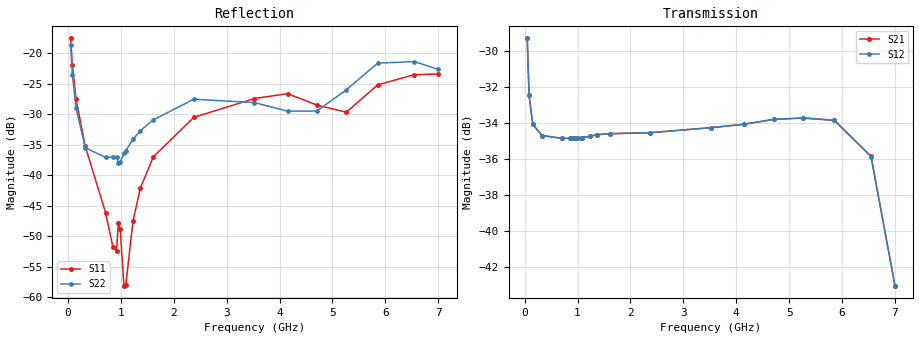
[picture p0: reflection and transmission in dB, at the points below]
! Integrated Device Technology
! Corporate Headquarters
! 6024 Silver Creek Valley Road
! San Jose, CA 95138  USA
! Phone:  1-408-284-8200
! Toll Free:  1-800-223-1366
! Webpage:  http://www.idt.com/
! Timing and RF Division
! 515 Groton Road, Suite 102
! Westford, MA 01886-6024
! Device:  F2258
! Description: Voltage Variable RF Attenuator
! Frequency:  50.0 -  6000.00 MHz
! Package:  3x3 mm Thin QFN Plastic Package: 16 pin
! Ports:  2 RF, 2 DC
!  Pin  1  = NC
!  Pin  2  = NC
!  Pin  3  = RF2  = Port 2
!  Pin  4  = GND
!  Pin  5  = Vdd
!  Pin  6  = NC
!  Pin  7  = VCTRL
!  Pin  8  = NC
!  Pin  9  = GND
!  Pin 10  = RF1  = Port 1
!  Pin 11  = NC
!  Pin 12  = NC
!  Pin 13  = NC
!  Pin 14  = NC
!  Pin 15  = NC
!  Pin 16  = NC
! Vcntrl:  1.960 Volts
! Vdd:  +3.300 Volts
! Current:  1.155 mA
! Data:  The device was measured on a the F2258 evaluation board which has
!  individual transmission lines to the RF pins.  Data was collected
!  using a calibrated network analyzer.  The evaluation board was
!  de-embedded using a TRL calibration technique.
!  The reference plane is the edge of the package pin.
! Misc:  SN 10
!  Action Tracker AT0285
! Date Measured:  2014-12-10
! Date:  2016-01-13  MJV
! Note:
!  Integrated Device Technology supplies this data as a sample of measured
!  data at the package pin for this product.  Your particular data for this
!  product may vary.
!  Data was taken at 25 degrees C.
!  Integrated Device Technology reserves the right to change this data at anytime.
!Freq_(GHz)  S11M_(dB)  S11P_(deg)  S21M_(dB)  S21P_(deg)  S12M_(dB)  S12P_(deg)  S22M_(dB)  S22P_(deg)
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# GHz S dB R 50
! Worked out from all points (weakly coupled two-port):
!   201 points, 50 MHz to 7 GHz, reference 50 ohm
!   highest |S21| = -29.28 dB at 50 MHz (marker M1); lowest = -43.0 dB at 7 GHz (marker M2)
!   lowest |S11| = -58.1 dB at 1.058 GHz (marker M3), VSWR 1.00, Z = 49.9 + j0.0533 ohm
!   |S11| at or under -10 dB: start of sweep to end of sweep
!   |S22| runs from -38.1 to -18.7 dB; largest |S21 - S12| = 6.1e-05
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0.05  -17.55 -110.9  -29.28 -66.0  -29.28 -66.0  -18.69 -106.9
0.08475  -21.97 -107.3  -32.45 -46.6  -32.45 -46.6  -23.57 -96.0
0.15425  -27.55 -107.8  -34.05 -28.3  -34.06 -28.3  -29.06 -82.4
0.328  -35.29 -114.7  -34.68 -14.9  -34.68 -14.9  -35.51 -51.1
0.71025  -46.14 -136.2  -34.83 -9.4  -34.84 -9.4  -37.08 2.5
0.84925  -51.76 -173.4  -34.83 -8.8  -34.84 -8.8  -37.00 9.1
0.91875  -52.42 149.7  -34.82 -8.7  -34.83 -8.7  -36.95 10.5
0.9535  -47.79 -162.2  -34.83 -8.6  -34.84 -8.6  -38.05 23.0
0.98825  -48.87 -173.7  -34.81 -8.5  -34.83 -8.5  -37.84 21.0
1.05775  -58.15 154.4  -34.80 -8.4  -34.81 -8.4  -36.39 20.5
1.0925  -58.08 117.0  -34.79 -8.4  -34.79 -8.4  -36.02 20.6
1.2315  -47.45 44.9  -34.72 -8.6  -34.72 -8.5  -34.09 19.0
1.3705  -42.08 36.4  -34.63 -9.1  -34.63 -9.1  -32.70 19.0
1.61375  -37.00 32.4  -34.57 -10.4  -34.58 -10.4  -30.93 17.0
2.37825  -30.52 47.9  -34.52 -14.3  -34.52 -14.3  -27.54 19.6
3.525  -27.43 91.5  -34.24 -21.2  -34.24 -21.2  -28.10 45.5
4.1505  -26.63 104.9  -34.05 -25.8  -34.05 -25.8  -29.50 55.7
4.7065  -28.50 95.6  -33.78 -30.6  -33.78 -30.6  -29.47 36.7
5.2625  -29.68 54.2  -33.70 -36.7  -33.71 -36.6  -26.00 2.3
5.85325  -25.19 29.8  -33.83 -47.0  -33.84 -47.0  -21.62 -13.7
6.54825  -23.51 45.0  -35.83 -66.9  -35.85 -66.9  -21.37 -46.6
7  -23.40 84.4  -43.02 -62.8  -43.02 -62.5  -22.64 -127.1
